VERSION 5.7 ;
  NOWIREEXTENSIONATPIN ON ;
  DIVIDERCHAR "/" ;
  BUSBITCHARS "[]" ;
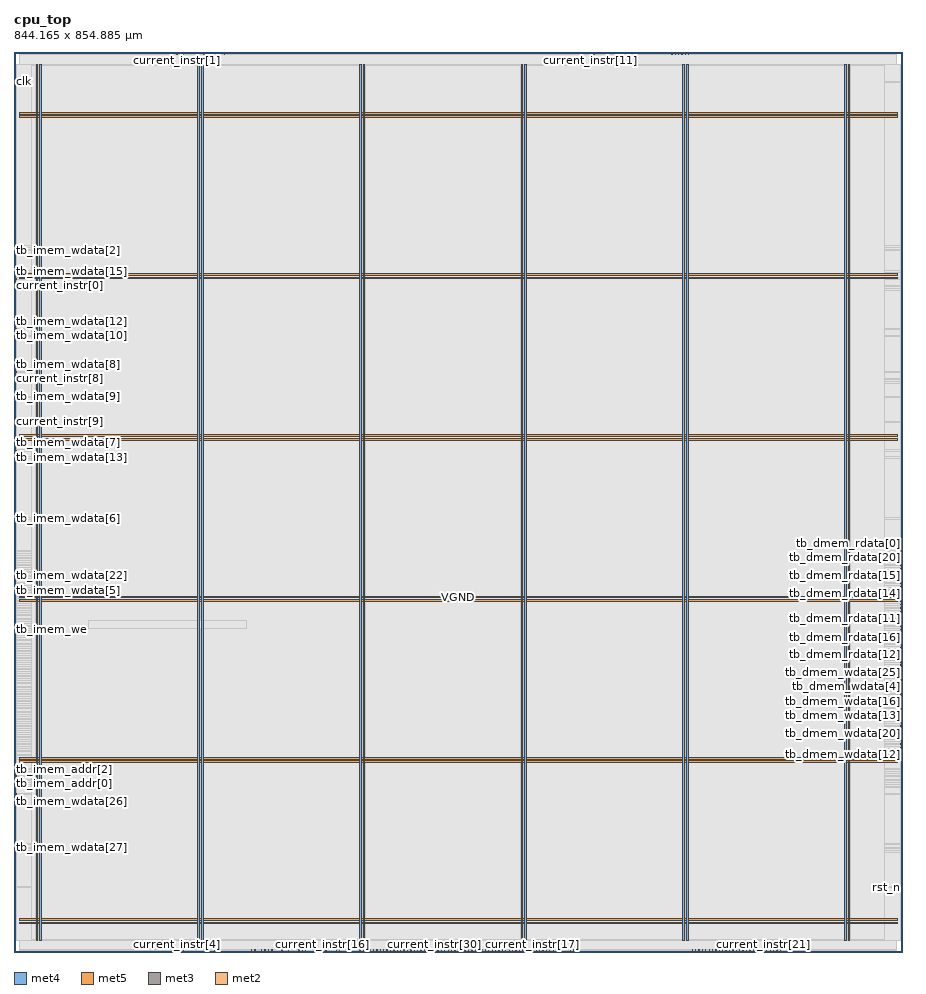
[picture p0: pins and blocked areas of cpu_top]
MACRO cpu_top
  CLASS BLOCK ;
  FOREIGN cpu_top ;
  ORIGIN 0.000 0.000 ;
  SIZE 844.165 BY 854.885 ;
  PIN VGND
    DIRECTION INOUT ;
    USE GROUND ;
    PORT
      LAYER met4 ;
        RECT 24.340 10.640 25.940 843.440 ;
    END
    PORT
      LAYER met4 ;
        RECT 177.940 10.640 179.540 843.440 ;
    END
    PORT
      LAYER met4 ;
        RECT 331.540 10.640 333.140 843.440 ;
    END
    PORT
      LAYER met4 ;
        RECT 485.140 10.640 486.740 843.440 ;
    END
    PORT
      LAYER met4 ;
        RECT 638.740 10.640 640.340 843.440 ;
    END
    PORT
      LAYER met4 ;
        RECT 792.340 10.640 793.940 843.440 ;
    END
    PORT
      LAYER met5 ;
        RECT 5.280 30.030 838.820 31.630 ;
    END
    PORT
      LAYER met5 ;
        RECT 5.280 183.210 838.820 184.810 ;
    END
    PORT
      LAYER met5 ;
        RECT 5.280 336.390 838.820 337.990 ;
    END
    PORT
      LAYER met5 ;
        RECT 5.280 489.570 838.820 491.170 ;
    END
    PORT
      LAYER met5 ;
        RECT 5.280 642.750 838.820 644.350 ;
    END
    PORT
      LAYER met5 ;
        RECT 5.280 795.930 838.820 797.530 ;
    END
  END VGND
  PIN VPWR
    DIRECTION INOUT ;
    USE POWER ;
    PORT
      LAYER met4 ;
        RECT 21.040 10.640 22.640 843.440 ;
    END
    PORT
      LAYER met4 ;
        RECT 174.640 10.640 176.240 843.440 ;
    END
    PORT
      LAYER met4 ;
        RECT 328.240 10.640 329.840 843.440 ;
    END
    PORT
      LAYER met4 ;
        RECT 481.840 10.640 483.440 843.440 ;
    END
    PORT
      LAYER met4 ;
        RECT 635.440 10.640 637.040 843.440 ;
    END
    PORT
      LAYER met4 ;
        RECT 789.040 10.640 790.640 843.440 ;
    END
    PORT
      LAYER met5 ;
        RECT 5.280 26.730 838.820 28.330 ;
    END
    PORT
      LAYER met5 ;
        RECT 5.280 179.910 838.820 181.510 ;
    END
    PORT
      LAYER met5 ;
        RECT 5.280 333.090 838.820 334.690 ;
    END
    PORT
      LAYER met5 ;
        RECT 5.280 486.270 838.820 487.870 ;
    END
    PORT
      LAYER met5 ;
        RECT 5.280 639.450 838.820 641.050 ;
    END
    PORT
      LAYER met5 ;
        RECT 5.280 792.630 838.820 794.230 ;
    END
  END VPWR
  PIN clk
    DIRECTION INPUT ;
    USE SIGNAL ;
    ANTENNAGATEAREA 0.852000 ;
    ANTENNADIFFAREA 0.434700 ;
    PORT
      LAYER met3 ;
        RECT 0.000 826.240 2.000 826.840 ;
    END
  END clk
  PIN current_instr[0]
    DIRECTION OUTPUT ;
    USE SIGNAL ;
    ANTENNADIFFAREA 0.445500 ;
    PORT
      LAYER met3 ;
        RECT 0.000 632.440 2.000 633.040 ;
    END
  END current_instr[0]
  PIN current_instr[10]
    DIRECTION OUTPUT ;
    USE SIGNAL ;
    ANTENNADIFFAREA 0.795200 ;
    PORT
      LAYER met2 ;
        RECT 499.190 0.000 499.470 2.000 ;
    END
  END current_instr[10]
  PIN current_instr[11]
    DIRECTION OUTPUT ;
    USE SIGNAL ;
    ANTENNADIFFAREA 0.795200 ;
    PORT
      LAYER met2 ;
        RECT 547.490 852.885 547.770 854.885 ;
    END
  END current_instr[11]
  PIN current_instr[12]
    DIRECTION OUTPUT ;
    USE SIGNAL ;
    ANTENNADIFFAREA 0.795200 ;
    PORT
      LAYER met2 ;
        RECT 254.470 0.000 254.750 2.000 ;
    END
  END current_instr[12]
  PIN current_instr[13]
    DIRECTION OUTPUT ;
    USE SIGNAL ;
    ANTENNADIFFAREA 0.795200 ;
    PORT
      LAYER met2 ;
        RECT 309.210 0.000 309.490 2.000 ;
    END
  END current_instr[13]
  PIN current_instr[14]
    DIRECTION OUTPUT ;
    USE SIGNAL ;
    ANTENNADIFFAREA 0.795200 ;
    PORT
      LAYER met2 ;
        RECT 505.630 0.000 505.910 2.000 ;
    END
  END current_instr[14]
  PIN current_instr[15]
    DIRECTION OUTPUT ;
    USE SIGNAL ;
    ANTENNADIFFAREA 0.795200 ;
    PORT
      LAYER met2 ;
        RECT 550.710 852.885 550.990 854.885 ;
    END
  END current_instr[15]
  PIN current_instr[16]
    DIRECTION OUTPUT ;
    USE SIGNAL ;
    ANTENNADIFFAREA 0.795200 ;
    PORT
      LAYER met2 ;
        RECT 293.110 0.000 293.390 2.000 ;
    END
  END current_instr[16]
  PIN current_instr[17]
    DIRECTION OUTPUT ;
    USE SIGNAL ;
    ANTENNADIFFAREA 0.795200 ;
    PORT
      LAYER met2 ;
        RECT 492.750 0.000 493.030 2.000 ;
    END
  END current_instr[17]
  PIN current_instr[18]
    DIRECTION OUTPUT ;
    USE SIGNAL ;
    ANTENNADIFFAREA 0.795200 ;
    PORT
      LAYER met2 ;
        RECT 508.850 0.000 509.130 2.000 ;
    END
  END current_instr[18]
  PIN current_instr[19]
    DIRECTION OUTPUT ;
    USE SIGNAL ;
    ANTENNADIFFAREA 0.795200 ;
    PORT
      LAYER met2 ;
        RECT 489.530 0.000 489.810 2.000 ;
    END
  END current_instr[19]
  PIN current_instr[1]
    DIRECTION OUTPUT ;
    USE SIGNAL ;
    ANTENNADIFFAREA 0.795200 ;
    PORT
      LAYER met2 ;
        RECT 154.650 852.885 154.930 854.885 ;
    END
  END current_instr[1]
  PIN current_instr[20]
    DIRECTION OUTPUT ;
    USE SIGNAL ;
    ANTENNADIFFAREA 0.795200 ;
    PORT
      LAYER met2 ;
        RECT 434.790 0.000 435.070 2.000 ;
    END
  END current_instr[20]
  PIN current_instr[21]
    DIRECTION OUTPUT ;
    USE SIGNAL ;
    ANTENNADIFFAREA 0.795200 ;
    PORT
      LAYER met2 ;
        RECT 711.710 0.000 711.990 2.000 ;
    END
  END current_instr[21]
  PIN current_instr[22]
    DIRECTION OUTPUT ;
    USE SIGNAL ;
    ANTENNADIFFAREA 0.795200 ;
    PORT
      LAYER met2 ;
        RECT 418.690 0.000 418.970 2.000 ;
    END
  END current_instr[22]
  PIN current_instr[23]
    DIRECTION OUTPUT ;
    USE SIGNAL ;
    ANTENNADIFFAREA 0.795200 ;
    PORT
      LAYER met2 ;
        RECT 479.870 0.000 480.150 2.000 ;
    END
  END current_instr[23]
  PIN current_instr[24]
    DIRECTION OUTPUT ;
    USE SIGNAL ;
    ANTENNADIFFAREA 0.795200 ;
    PORT
      LAYER met2 ;
        RECT 476.650 0.000 476.930 2.000 ;
    END
  END current_instr[24]
  PIN current_instr[25]
    DIRECTION OUTPUT ;
    USE SIGNAL ;
    ANTENNADIFFAREA 0.795200 ;
    PORT
      LAYER met2 ;
        RECT 483.090 0.000 483.370 2.000 ;
    END
  END current_instr[25]
  PIN current_instr[26]
    DIRECTION OUTPUT ;
    USE SIGNAL ;
    ANTENNADIFFAREA 0.795200 ;
    PORT
      LAYER met2 ;
        RECT 441.230 0.000 441.510 2.000 ;
    END
  END current_instr[26]
  PIN current_instr[27]
    DIRECTION OUTPUT ;
    USE SIGNAL ;
    ANTENNADIFFAREA 0.795200 ;
    PORT
      LAYER met2 ;
        RECT 438.010 0.000 438.290 2.000 ;
    END
  END current_instr[27]
  PIN current_instr[28]
    DIRECTION OUTPUT ;
    USE SIGNAL ;
    ANTENNADIFFAREA 0.795200 ;
    PORT
      LAYER met2 ;
        RECT 409.030 0.000 409.310 2.000 ;
    END
  END current_instr[28]
  PIN current_instr[29]
    DIRECTION OUTPUT ;
    USE SIGNAL ;
    ANTENNADIFFAREA 0.795200 ;
    PORT
      LAYER met2 ;
        RECT 425.130 0.000 425.410 2.000 ;
    END
  END current_instr[29]
  PIN current_instr[2]
    DIRECTION OUTPUT ;
    USE SIGNAL ;
    ANTENNADIFFAREA 0.795200 ;
    PORT
      LAYER met2 ;
        RECT 199.730 852.885 200.010 854.885 ;
    END
  END current_instr[2]
  PIN current_instr[30]
    DIRECTION OUTPUT ;
    USE SIGNAL ;
    ANTENNADIFFAREA 0.795200 ;
    PORT
      LAYER met2 ;
        RECT 399.370 0.000 399.650 2.000 ;
    END
  END current_instr[30]
  PIN current_instr[31]
    DIRECTION OUTPUT ;
    USE SIGNAL ;
    ANTENNADIFFAREA 0.795200 ;
    PORT
      LAYER met2 ;
        RECT 402.590 0.000 402.870 2.000 ;
    END
  END current_instr[31]
  PIN current_instr[3]
    DIRECTION OUTPUT ;
    USE SIGNAL ;
    ANTENNADIFFAREA 0.795200 ;
    PORT
      LAYER met2 ;
        RECT 161.090 852.885 161.370 854.885 ;
    END
  END current_instr[3]
  PIN current_instr[4]
    DIRECTION OUTPUT ;
    USE SIGNAL ;
    ANTENNADIFFAREA 0.795200 ;
    PORT
      LAYER met2 ;
        RECT 154.650 0.000 154.930 2.000 ;
    END
  END current_instr[4]
  PIN current_instr[5]
    DIRECTION OUTPUT ;
    USE SIGNAL ;
    ANTENNADIFFAREA 0.795200 ;
    PORT
      LAYER met2 ;
        RECT 157.870 0.000 158.150 2.000 ;
    END
  END current_instr[5]
  PIN current_instr[6]
    DIRECTION OUTPUT ;
    USE SIGNAL ;
    ANTENNADIFFAREA 0.795200 ;
    PORT
      LAYER met2 ;
        RECT 235.150 0.000 235.430 2.000 ;
    END
  END current_instr[6]
  PIN current_instr[7]
    DIRECTION OUTPUT ;
    USE SIGNAL ;
    ANTENNADIFFAREA 0.795200 ;
    PORT
      LAYER met2 ;
        RECT 161.090 0.000 161.370 2.000 ;
    END
  END current_instr[7]
  PIN current_instr[8]
    DIRECTION OUTPUT ;
    USE SIGNAL ;
    ANTENNADIFFAREA 0.445500 ;
    PORT
      LAYER met3 ;
        RECT 0.000 544.040 2.000 544.640 ;
    END
  END current_instr[8]
  PIN current_instr[9]
    DIRECTION OUTPUT ;
    USE SIGNAL ;
    ANTENNADIFFAREA 0.445500 ;
    PORT
      LAYER met3 ;
        RECT 0.000 503.240 2.000 503.840 ;
    END
  END current_instr[9]
  PIN pc_out[0]
    DIRECTION OUTPUT ;
    USE SIGNAL ;
    ANTENNADIFFAREA 0.795200 ;
    PORT
      LAYER met2 ;
        RECT 270.570 0.000 270.850 2.000 ;
    END
  END pc_out[0]
  PIN pc_out[10]
    DIRECTION OUTPUT ;
    USE SIGNAL ;
    ANTENNADIFFAREA 0.795200 ;
    PORT
      LAYER met2 ;
        RECT 328.530 0.000 328.810 2.000 ;
    END
  END pc_out[10]
  PIN pc_out[11]
    DIRECTION OUTPUT ;
    USE SIGNAL ;
    ANTENNADIFFAREA 0.795200 ;
    PORT
      LAYER met2 ;
        RECT 389.710 0.000 389.990 2.000 ;
    END
  END pc_out[11]
  PIN pc_out[12]
    DIRECTION OUTPUT ;
    USE SIGNAL ;
    ANTENNADIFFAREA 0.795200 ;
    PORT
      LAYER met2 ;
        RECT 412.250 0.000 412.530 2.000 ;
    END
  END pc_out[12]
  PIN pc_out[13]
    DIRECTION OUTPUT ;
    USE SIGNAL ;
    ANTENNADIFFAREA 0.795200 ;
    PORT
      LAYER met2 ;
        RECT 392.930 0.000 393.210 2.000 ;
    END
  END pc_out[13]
  PIN pc_out[14]
    DIRECTION OUTPUT ;
    USE SIGNAL ;
    ANTENNADIFFAREA 0.795200 ;
    PORT
      LAYER met2 ;
        RECT 334.970 0.000 335.250 2.000 ;
    END
  END pc_out[14]
  PIN pc_out[15]
    DIRECTION OUTPUT ;
    USE SIGNAL ;
    ANTENNADIFFAREA 0.795200 ;
    PORT
      LAYER met2 ;
        RECT 331.750 0.000 332.030 2.000 ;
    END
  END pc_out[15]
  PIN pc_out[16]
    DIRECTION OUTPUT ;
    USE SIGNAL ;
    ANTENNADIFFAREA 0.795200 ;
    PORT
      LAYER met2 ;
        RECT 338.190 0.000 338.470 2.000 ;
    END
  END pc_out[16]
  PIN pc_out[17]
    DIRECTION OUTPUT ;
    USE SIGNAL ;
    ANTENNADIFFAREA 0.795200 ;
    PORT
      LAYER met2 ;
        RECT 357.510 0.000 357.790 2.000 ;
    END
  END pc_out[17]
  PIN pc_out[18]
    DIRECTION OUTPUT ;
    USE SIGNAL ;
    ANTENNADIFFAREA 0.795200 ;
    PORT
      LAYER met2 ;
        RECT 373.610 0.000 373.890 2.000 ;
    END
  END pc_out[18]
  PIN pc_out[19]
    DIRECTION OUTPUT ;
    USE SIGNAL ;
    ANTENNADIFFAREA 0.795200 ;
    PORT
      LAYER met2 ;
        RECT 370.390 0.000 370.670 2.000 ;
    END
  END pc_out[19]
  PIN pc_out[1]
    DIRECTION OUTPUT ;
    USE SIGNAL ;
    ANTENNADIFFAREA 0.795200 ;
    PORT
      LAYER met2 ;
        RECT 238.370 0.000 238.650 2.000 ;
    END
  END pc_out[1]
  PIN pc_out[20]
    DIRECTION OUTPUT ;
    USE SIGNAL ;
    ANTENNADIFFAREA 0.795200 ;
    PORT
      LAYER met2 ;
        RECT 363.950 0.000 364.230 2.000 ;
    END
  END pc_out[20]
  PIN pc_out[21]
    DIRECTION OUTPUT ;
    USE SIGNAL ;
    ANTENNADIFFAREA 0.795200 ;
    PORT
      LAYER met2 ;
        RECT 376.830 0.000 377.110 2.000 ;
    END
  END pc_out[21]
  PIN pc_out[22]
    DIRECTION OUTPUT ;
    USE SIGNAL ;
    ANTENNADIFFAREA 0.795200 ;
    PORT
      LAYER met2 ;
        RECT 341.410 0.000 341.690 2.000 ;
    END
  END pc_out[22]
  PIN pc_out[23]
    DIRECTION OUTPUT ;
    USE SIGNAL ;
    ANTENNADIFFAREA 0.795200 ;
    PORT
      LAYER met2 ;
        RECT 380.050 0.000 380.330 2.000 ;
    END
  END pc_out[23]
  PIN pc_out[24]
    DIRECTION OUTPUT ;
    USE SIGNAL ;
    ANTENNADIFFAREA 0.795200 ;
    PORT
      LAYER met2 ;
        RECT 383.270 0.000 383.550 2.000 ;
    END
  END pc_out[24]
  PIN pc_out[25]
    DIRECTION OUTPUT ;
    USE SIGNAL ;
    ANTENNADIFFAREA 0.795200 ;
    PORT
      LAYER met2 ;
        RECT 386.490 0.000 386.770 2.000 ;
    END
  END pc_out[25]
  PIN pc_out[26]
    DIRECTION OUTPUT ;
    USE SIGNAL ;
    ANTENNADIFFAREA 0.795200 ;
    PORT
      LAYER met2 ;
        RECT 415.470 0.000 415.750 2.000 ;
    END
  END pc_out[26]
  PIN pc_out[27]
    DIRECTION OUTPUT ;
    USE SIGNAL ;
    ANTENNADIFFAREA 0.795200 ;
    PORT
      LAYER met2 ;
        RECT 431.570 0.000 431.850 2.000 ;
    END
  END pc_out[27]
  PIN pc_out[28]
    DIRECTION OUTPUT ;
    USE SIGNAL ;
    ANTENNADIFFAREA 0.795200 ;
    PORT
      LAYER met2 ;
        RECT 421.910 0.000 422.190 2.000 ;
    END
  END pc_out[28]
  PIN pc_out[29]
    DIRECTION OUTPUT ;
    USE SIGNAL ;
    ANTENNADIFFAREA 0.795200 ;
    PORT
      LAYER met2 ;
        RECT 405.810 0.000 406.090 2.000 ;
    END
  END pc_out[29]
  PIN pc_out[2]
    DIRECTION OUTPUT ;
    USE SIGNAL ;
    ANTENNADIFFAREA 0.795200 ;
    PORT
      LAYER met2 ;
        RECT 241.590 0.000 241.870 2.000 ;
    END
  END pc_out[2]
  PIN pc_out[30]
    DIRECTION OUTPUT ;
    USE SIGNAL ;
    ANTENNADIFFAREA 0.795200 ;
    PORT
      LAYER met2 ;
        RECT 396.150 0.000 396.430 2.000 ;
    END
  END pc_out[30]
  PIN pc_out[31]
    DIRECTION OUTPUT ;
    USE SIGNAL ;
    ANTENNADIFFAREA 0.795200 ;
    PORT
      LAYER met2 ;
        RECT 428.350 0.000 428.630 2.000 ;
    END
  END pc_out[31]
  PIN pc_out[3]
    DIRECTION OUTPUT ;
    USE SIGNAL ;
    ANTENNADIFFAREA 0.795200 ;
    PORT
      LAYER met2 ;
        RECT 244.810 0.000 245.090 2.000 ;
    END
  END pc_out[3]
  PIN pc_out[4]
    DIRECTION OUTPUT ;
    USE SIGNAL ;
    ANTENNADIFFAREA 0.795200 ;
    PORT
      LAYER met2 ;
        RECT 225.490 0.000 225.770 2.000 ;
    END
  END pc_out[4]
  PIN pc_out[5]
    DIRECTION OUTPUT ;
    USE SIGNAL ;
    ANTENNADIFFAREA 0.795200 ;
    PORT
      LAYER met2 ;
        RECT 228.710 0.000 228.990 2.000 ;
    END
  END pc_out[5]
  PIN pc_out[6]
    DIRECTION OUTPUT ;
    USE SIGNAL ;
    ANTENNADIFFAREA 0.795200 ;
    PORT
      LAYER met2 ;
        RECT 344.630 0.000 344.910 2.000 ;
    END
  END pc_out[6]
  PIN pc_out[7]
    DIRECTION OUTPUT ;
    USE SIGNAL ;
    ANTENNADIFFAREA 0.795200 ;
    PORT
      LAYER met2 ;
        RECT 354.290 0.000 354.570 2.000 ;
    END
  END pc_out[7]
  PIN pc_out[8]
    DIRECTION OUTPUT ;
    USE SIGNAL ;
    ANTENNADIFFAREA 0.795200 ;
    PORT
      LAYER met2 ;
        RECT 360.730 0.000 361.010 2.000 ;
    END
  END pc_out[8]
  PIN pc_out[9]
    DIRECTION OUTPUT ;
    USE SIGNAL ;
    ANTENNADIFFAREA 0.795200 ;
    PORT
      LAYER met2 ;
        RECT 367.170 0.000 367.450 2.000 ;
    END
  END pc_out[9]
  PIN rst_n
    DIRECTION INPUT ;
    USE SIGNAL ;
    ANTENNAGATEAREA 0.213000 ;
    ANTENNADIFFAREA 0.434700 ;
    PORT
      LAYER met3 ;
        RECT 842.165 61.240 844.165 61.840 ;
    END
  END rst_n
  PIN tb_dmem_addr[0]
    DIRECTION INPUT ;
    USE SIGNAL ;
    ANTENNAGATEAREA 0.213000 ;
    ANTENNADIFFAREA 0.434700 ;
    PORT
      LAYER met2 ;
        RECT 634.430 852.885 634.710 854.885 ;
    END
  END tb_dmem_addr[0]
  PIN tb_dmem_addr[1]
    DIRECTION INPUT ;
    USE SIGNAL ;
    ANTENNAGATEAREA 0.213000 ;
    ANTENNADIFFAREA 0.434700 ;
    PORT
      LAYER met2 ;
        RECT 631.210 852.885 631.490 854.885 ;
    END
  END tb_dmem_addr[1]
  PIN tb_dmem_addr[2]
    DIRECTION INPUT ;
    USE SIGNAL ;
    ANTENNAGATEAREA 0.213000 ;
    ANTENNADIFFAREA 0.434700 ;
    PORT
      LAYER met2 ;
        RECT 640.870 852.885 641.150 854.885 ;
    END
  END tb_dmem_addr[2]
  PIN tb_dmem_addr[3]
    DIRECTION INPUT ;
    USE SIGNAL ;
    ANTENNAGATEAREA 0.213000 ;
    ANTENNADIFFAREA 0.434700 ;
    PORT
      LAYER met2 ;
        RECT 637.650 852.885 637.930 854.885 ;
    END
  END tb_dmem_addr[3]
  PIN tb_dmem_addr[4]
    DIRECTION INPUT ;
    USE SIGNAL ;
    ANTENNAGATEAREA 0.159000 ;
    ANTENNADIFFAREA 0.434700 ;
    PORT
      LAYER met2 ;
        RECT 624.770 852.885 625.050 854.885 ;
    END
  END tb_dmem_addr[4]
  PIN tb_dmem_addr[5]
    DIRECTION INPUT ;
    USE SIGNAL ;
    ANTENNAGATEAREA 0.159000 ;
    ANTENNADIFFAREA 0.434700 ;
    PORT
      LAYER met2 ;
        RECT 627.990 852.885 628.270 854.885 ;
    END
  END tb_dmem_addr[5]
  PIN tb_dmem_rdata[0]
    DIRECTION OUTPUT ;
    USE SIGNAL ;
    ANTENNADIFFAREA 0.445500 ;
    PORT
      LAYER met3 ;
        RECT 842.165 380.840 844.165 381.440 ;
    END
  END tb_dmem_rdata[0]
  PIN tb_dmem_rdata[10]
    DIRECTION OUTPUT ;
    USE SIGNAL ;
    ANTENNADIFFAREA 0.445500 ;
    PORT
      LAYER met3 ;
        RECT 842.165 360.440 844.165 361.040 ;
    END
  END tb_dmem_rdata[10]
  PIN tb_dmem_rdata[11]
    DIRECTION OUTPUT ;
    USE SIGNAL ;
    ANTENNADIFFAREA 0.445500 ;
    PORT
      LAYER met3 ;
        RECT 842.165 316.240 844.165 316.840 ;
    END
  END tb_dmem_rdata[11]
  PIN tb_dmem_rdata[12]
    DIRECTION OUTPUT ;
    USE SIGNAL ;
    ANTENNADIFFAREA 0.445500 ;
    PORT
      LAYER met3 ;
        RECT 842.165 282.240 844.165 282.840 ;
    END
  END tb_dmem_rdata[12]
  PIN tb_dmem_rdata[13]
    DIRECTION OUTPUT ;
    USE SIGNAL ;
    ANTENNADIFFAREA 0.445500 ;
    PORT
      LAYER met3 ;
        RECT 842.165 295.840 844.165 296.440 ;
    END
  END tb_dmem_rdata[13]
  PIN tb_dmem_rdata[14]
    DIRECTION OUTPUT ;
    USE SIGNAL ;
    ANTENNADIFFAREA 0.445500 ;
    PORT
      LAYER met3 ;
        RECT 842.165 340.040 844.165 340.640 ;
    END
  END tb_dmem_rdata[14]
  PIN tb_dmem_rdata[15]
    DIRECTION OUTPUT ;
    USE SIGNAL ;
    ANTENNADIFFAREA 0.445500 ;
    PORT
      LAYER met3 ;
        RECT 842.165 357.040 844.165 357.640 ;
    END
  END tb_dmem_rdata[15]
  PIN tb_dmem_rdata[16]
    DIRECTION OUTPUT ;
    USE SIGNAL ;
    ANTENNADIFFAREA 0.445500 ;
    PORT
      LAYER met3 ;
        RECT 842.165 306.040 844.165 306.640 ;
    END
  END tb_dmem_rdata[16]
  PIN tb_dmem_rdata[17]
    DIRECTION OUTPUT ;
    USE SIGNAL ;
    ANTENNADIFFAREA 0.445500 ;
    PORT
      LAYER met3 ;
        RECT 842.165 323.040 844.165 323.640 ;
    END
  END tb_dmem_rdata[17]
  PIN tb_dmem_rdata[18]
    DIRECTION OUTPUT ;
    USE SIGNAL ;
    ANTENNADIFFAREA 0.445500 ;
    PORT
      LAYER met3 ;
        RECT 842.165 370.640 844.165 371.240 ;
    END
  END tb_dmem_rdata[18]
  PIN tb_dmem_rdata[19]
    DIRECTION OUTPUT ;
    USE SIGNAL ;
    ANTENNADIFFAREA 0.445500 ;
    PORT
      LAYER met3 ;
        RECT 842.165 336.640 844.165 337.240 ;
    END
  END tb_dmem_rdata[19]
  PIN tb_dmem_rdata[1]
    DIRECTION OUTPUT ;
    USE SIGNAL ;
    ANTENNADIFFAREA 0.795200 ;
    PORT
      LAYER met2 ;
        RECT 447.670 0.000 447.950 2.000 ;
    END
  END tb_dmem_rdata[1]
  PIN tb_dmem_rdata[20]
    DIRECTION OUTPUT ;
    USE SIGNAL ;
    ANTENNADIFFAREA 0.445500 ;
    PORT
      LAYER met3 ;
        RECT 842.165 367.240 844.165 367.840 ;
    END
  END tb_dmem_rdata[20]
  PIN tb_dmem_rdata[21]
    DIRECTION OUTPUT ;
    USE SIGNAL ;
    ANTENNADIFFAREA 0.445500 ;
    PORT
      LAYER met3 ;
        RECT 842.165 289.040 844.165 289.640 ;
    END
  END tb_dmem_rdata[21]
  PIN tb_dmem_rdata[22]
    DIRECTION OUTPUT ;
    USE SIGNAL ;
    ANTENNADIFFAREA 0.445500 ;
    PORT
      LAYER met3 ;
        RECT 842.165 333.240 844.165 333.840 ;
    END
  END tb_dmem_rdata[22]
  PIN tb_dmem_rdata[23]
    DIRECTION OUTPUT ;
    USE SIGNAL ;
    ANTENNADIFFAREA 0.445500 ;
    PORT
      LAYER met3 ;
        RECT 842.165 326.440 844.165 327.040 ;
    END
  END tb_dmem_rdata[23]
  PIN tb_dmem_rdata[24]
    DIRECTION OUTPUT ;
    USE SIGNAL ;
    ANTENNADIFFAREA 0.445500 ;
    PORT
      LAYER met3 ;
        RECT 842.165 312.840 844.165 313.440 ;
    END
  END tb_dmem_rdata[24]
  PIN tb_dmem_rdata[25]
    DIRECTION OUTPUT ;
    USE SIGNAL ;
    ANTENNADIFFAREA 0.445500 ;
    PORT
      LAYER met3 ;
        RECT 842.165 302.640 844.165 303.240 ;
    END
  END tb_dmem_rdata[25]
  PIN tb_dmem_rdata[26]
    DIRECTION OUTPUT ;
    USE SIGNAL ;
    ANTENNADIFFAREA 0.445500 ;
    PORT
      LAYER met3 ;
        RECT 842.165 299.240 844.165 299.840 ;
    END
  END tb_dmem_rdata[26]
  PIN tb_dmem_rdata[27]
    DIRECTION OUTPUT ;
    USE SIGNAL ;
    ANTENNADIFFAREA 0.445500 ;
    PORT
      LAYER met3 ;
        RECT 842.165 374.040 844.165 374.640 ;
    END
  END tb_dmem_rdata[27]
  PIN tb_dmem_rdata[28]
    DIRECTION OUTPUT ;
    USE SIGNAL ;
    ANTENNADIFFAREA 0.445500 ;
    PORT
      LAYER met3 ;
        RECT 842.165 285.640 844.165 286.240 ;
    END
  END tb_dmem_rdata[28]
  PIN tb_dmem_rdata[29]
    DIRECTION OUTPUT ;
    USE SIGNAL ;
    ANTENNADIFFAREA 0.445500 ;
    PORT
      LAYER met3 ;
        RECT 842.165 353.640 844.165 354.240 ;
    END
  END tb_dmem_rdata[29]
  PIN tb_dmem_rdata[2]
    DIRECTION OUTPUT ;
    USE SIGNAL ;
    ANTENNADIFFAREA 0.795200 ;
    PORT
      LAYER met2 ;
        RECT 444.450 0.000 444.730 2.000 ;
    END
  END tb_dmem_rdata[2]
  PIN tb_dmem_rdata[30]
    DIRECTION OUTPUT ;
    USE SIGNAL ;
    ANTENNADIFFAREA 0.445500 ;
    PORT
      LAYER met3 ;
        RECT 842.165 350.240 844.165 350.840 ;
    END
  END tb_dmem_rdata[30]
  PIN tb_dmem_rdata[31]
    DIRECTION OUTPUT ;
    USE SIGNAL ;
    ANTENNADIFFAREA 0.445500 ;
    PORT
      LAYER met3 ;
        RECT 842.165 343.440 844.165 344.040 ;
    END
  END tb_dmem_rdata[31]
  PIN tb_dmem_rdata[3]
    DIRECTION OUTPUT ;
    USE SIGNAL ;
    ANTENNADIFFAREA 0.445500 ;
    PORT
      LAYER met3 ;
        RECT 842.165 309.440 844.165 310.040 ;
    END
  END tb_dmem_rdata[3]
  PIN tb_dmem_rdata[4]
    DIRECTION OUTPUT ;
    USE SIGNAL ;
    ANTENNADIFFAREA 0.795200 ;
    PORT
      LAYER met2 ;
        RECT 473.430 0.000 473.710 2.000 ;
    END
  END tb_dmem_rdata[4]
  PIN tb_dmem_rdata[5]
    DIRECTION OUTPUT ;
    USE SIGNAL ;
    ANTENNADIFFAREA 0.445500 ;
    PORT
      LAYER met3 ;
        RECT 842.165 329.840 844.165 330.440 ;
    END
  END tb_dmem_rdata[5]
  PIN tb_dmem_rdata[6]
    DIRECTION OUTPUT ;
    USE SIGNAL ;
    ANTENNADIFFAREA 0.445500 ;
    PORT
      LAYER met3 ;
        RECT 842.165 319.640 844.165 320.240 ;
    END
  END tb_dmem_rdata[6]
  PIN tb_dmem_rdata[7]
    DIRECTION OUTPUT ;
    USE SIGNAL ;
    ANTENNADIFFAREA 0.795200 ;
    PORT
      LAYER met2 ;
        RECT 457.330 0.000 457.610 2.000 ;
    END
  END tb_dmem_rdata[7]
  PIN tb_dmem_rdata[8]
    DIRECTION OUTPUT ;
    USE SIGNAL ;
    ANTENNADIFFAREA 0.445500 ;
    PORT
      LAYER met3 ;
        RECT 842.165 363.840 844.165 364.440 ;
    END
  END tb_dmem_rdata[8]
  PIN tb_dmem_rdata[9]
    DIRECTION OUTPUT ;
    USE SIGNAL ;
    ANTENNADIFFAREA 0.445500 ;
    PORT
      LAYER met3 ;
        RECT 842.165 292.440 844.165 293.040 ;
    END
  END tb_dmem_rdata[9]
  PIN tb_dmem_re
    DIRECTION INPUT ;
    USE SIGNAL ;
    ANTENNAGATEAREA 0.213000 ;
    ANTENNADIFFAREA 0.434700 ;
    PORT
      LAYER met3 ;
        RECT 842.165 346.840 844.165 347.440 ;
    END
  END tb_dmem_re
  PIN tb_dmem_wdata[0]
    DIRECTION INPUT ;
    USE SIGNAL ;
    ANTENNAGATEAREA 0.213000 ;
    ANTENNADIFFAREA 0.434700 ;
    PORT
      LAYER met2 ;
        RECT 463.770 0.000 464.050 2.000 ;
    END
  END tb_dmem_wdata[0]
  PIN tb_dmem_wdata[10]
    DIRECTION INPUT ;
    USE SIGNAL ;
    ANTENNAGATEAREA 0.213000 ;
    ANTENNADIFFAREA 0.434700 ;
    PORT
      LAYER met3 ;
        RECT 842.165 183.640 844.165 184.240 ;
    END
  END tb_dmem_wdata[10]
  PIN tb_dmem_wdata[11]
    DIRECTION INPUT ;
    USE SIGNAL ;
    ANTENNAGATEAREA 0.213000 ;
    ANTENNADIFFAREA 0.434700 ;
    PORT
      LAYER met3 ;
        RECT 842.165 275.440 844.165 276.040 ;
    END
  END tb_dmem_wdata[11]
  PIN tb_dmem_wdata[12]
    DIRECTION INPUT ;
    USE SIGNAL ;
    ANTENNAGATEAREA 0.159000 ;
    ANTENNADIFFAREA 0.434700 ;
    PORT
      LAYER met3 ;
        RECT 842.165 187.040 844.165 187.640 ;
    END
  END tb_dmem_wdata[12]
  PIN tb_dmem_wdata[13]
    DIRECTION INPUT ;
    USE SIGNAL ;
    ANTENNAGATEAREA 0.159000 ;
    ANTENNADIFFAREA 0.434700 ;
    PORT
      LAYER met3 ;
        RECT 842.165 224.440 844.165 225.040 ;
    END
  END tb_dmem_wdata[13]
  PIN tb_dmem_wdata[14]
    DIRECTION INPUT ;
    USE SIGNAL ;
    ANTENNAGATEAREA 0.213000 ;
    ANTENNADIFFAREA 0.434700 ;
    PORT
      LAYER met3 ;
        RECT 842.165 227.840 844.165 228.440 ;
    END
  END tb_dmem_wdata[14]
  PIN tb_dmem_wdata[15]
    DIRECTION INPUT ;
    USE SIGNAL ;
    ANTENNAGATEAREA 0.213000 ;
    ANTENNADIFFAREA 0.434700 ;
    PORT
      LAYER met3 ;
        RECT 842.165 221.040 844.165 221.640 ;
    END
  END tb_dmem_wdata[15]
  PIN tb_dmem_wdata[16]
    DIRECTION INPUT ;
    USE SIGNAL ;
    ANTENNAGATEAREA 0.213000 ;
    ANTENNADIFFAREA 0.434700 ;
    PORT
      LAYER met3 ;
        RECT 842.165 238.040 844.165 238.640 ;
    END
  END tb_dmem_wdata[16]
  PIN tb_dmem_wdata[17]
    DIRECTION INPUT ;
    USE SIGNAL ;
    ANTENNAGATEAREA 0.213000 ;
    ANTENNADIFFAREA 0.434700 ;
    PORT
      LAYER met3 ;
        RECT 842.165 255.040 844.165 255.640 ;
    END
  END tb_dmem_wdata[17]
  PIN tb_dmem_wdata[18]
    DIRECTION INPUT ;
    USE SIGNAL ;
    ANTENNAGATEAREA 0.213000 ;
    ANTENNADIFFAREA 0.434700 ;
    PORT
      LAYER met3 ;
        RECT 842.165 190.440 844.165 191.040 ;
    END
  END tb_dmem_wdata[18]
  PIN tb_dmem_wdata[19]
    DIRECTION INPUT ;
    USE SIGNAL ;
    ANTENNAGATEAREA 0.213000 ;
    ANTENNADIFFAREA 0.434700 ;
    PORT
      LAYER met3 ;
        RECT 842.165 217.640 844.165 218.240 ;
    END
  END tb_dmem_wdata[19]
  PIN tb_dmem_wdata[1]
    DIRECTION INPUT ;
    USE SIGNAL ;
    ANTENNAGATEAREA 0.213000 ;
    ANTENNADIFFAREA 0.434700 ;
    PORT
      LAYER met2 ;
        RECT 454.110 0.000 454.390 2.000 ;
    END
  END tb_dmem_wdata[1]
  PIN tb_dmem_wdata[20]
    DIRECTION INPUT ;
    USE SIGNAL ;
    ANTENNAGATEAREA 0.213000 ;
    ANTENNADIFFAREA 0.434700 ;
    PORT
      LAYER met3 ;
        RECT 842.165 214.240 844.165 214.840 ;
    END
  END tb_dmem_wdata[20]
  PIN tb_dmem_wdata[21]
    DIRECTION INPUT ;
    USE SIGNAL ;
    ANTENNAGATEAREA 0.213000 ;
    ANTENNADIFFAREA 0.434700 ;
    PORT
      LAYER met3 ;
        RECT 842.165 210.840 844.165 211.440 ;
    END
  END tb_dmem_wdata[21]
  PIN tb_dmem_wdata[22]
    DIRECTION INPUT ;
    USE SIGNAL ;
    ANTENNAGATEAREA 0.126000 ;
    ANTENNADIFFAREA 0.434700 ;
    PORT
      LAYER met3 ;
        RECT 842.165 278.840 844.165 279.440 ;
    END
  END tb_dmem_wdata[22]
  PIN tb_dmem_wdata[23]
    DIRECTION INPUT ;
    USE SIGNAL ;
    ANTENNAGATEAREA 0.196500 ;
    ANTENNADIFFAREA 0.434700 ;
    PORT
      LAYER met3 ;
        RECT 842.165 258.440 844.165 259.040 ;
    END
  END tb_dmem_wdata[23]
  PIN tb_dmem_wdata[24]
    DIRECTION INPUT ;
    USE SIGNAL ;
    ANTENNAGATEAREA 0.196500 ;
    ANTENNADIFFAREA 0.434700 ;
    PORT
      LAYER met3 ;
        RECT 842.165 234.640 844.165 235.240 ;
    END
  END tb_dmem_wdata[24]
  PIN tb_dmem_wdata[25]
    DIRECTION INPUT ;
    USE SIGNAL ;
    ANTENNAGATEAREA 0.196500 ;
    ANTENNADIFFAREA 0.434700 ;
    PORT
      LAYER met3 ;
        RECT 842.165 265.240 844.165 265.840 ;
    END
  END tb_dmem_wdata[25]
  PIN tb_dmem_wdata[26]
    DIRECTION INPUT ;
    USE SIGNAL ;
    ANTENNAGATEAREA 0.213000 ;
    ANTENNADIFFAREA 0.434700 ;
    PORT
      LAYER met3 ;
        RECT 842.165 207.440 844.165 208.040 ;
    END
  END tb_dmem_wdata[26]
  PIN tb_dmem_wdata[27]
    DIRECTION INPUT ;
    USE SIGNAL ;
    ANTENNAGATEAREA 0.196500 ;
    ANTENNADIFFAREA 0.434700 ;
    PORT
      LAYER met3 ;
        RECT 842.165 261.840 844.165 262.440 ;
    END
  END tb_dmem_wdata[27]
  PIN tb_dmem_wdata[28]
    DIRECTION INPUT ;
    USE SIGNAL ;
    ANTENNAGATEAREA 0.126000 ;
    ANTENNADIFFAREA 0.434700 ;
    PORT
      LAYER met3 ;
        RECT 842.165 204.040 844.165 204.640 ;
    END
  END tb_dmem_wdata[28]
  PIN tb_dmem_wdata[29]
    DIRECTION INPUT ;
    USE SIGNAL ;
    ANTENNAGATEAREA 0.213000 ;
    ANTENNADIFFAREA 0.434700 ;
    PORT
      LAYER met3 ;
        RECT 842.165 200.640 844.165 201.240 ;
    END
  END tb_dmem_wdata[29]
  PIN tb_dmem_wdata[2]
    DIRECTION INPUT ;
    USE SIGNAL ;
    ANTENNAGATEAREA 0.213000 ;
    ANTENNADIFFAREA 0.434700 ;
    PORT
      LAYER met2 ;
        RECT 450.890 0.000 451.170 2.000 ;
    END
  END tb_dmem_wdata[2]
  PIN tb_dmem_wdata[30]
    DIRECTION INPUT ;
    USE SIGNAL ;
    ANTENNAGATEAREA 0.159000 ;
    ANTENNADIFFAREA 0.434700 ;
    PORT
      LAYER met3 ;
        RECT 842.165 241.440 844.165 242.040 ;
    END
  END tb_dmem_wdata[30]
  PIN tb_dmem_wdata[31]
    DIRECTION INPUT ;
    USE SIGNAL ;
    ANTENNAGATEAREA 0.159000 ;
    ANTENNADIFFAREA 0.434700 ;
    PORT
      LAYER met3 ;
        RECT 842.165 197.240 844.165 197.840 ;
    END
  END tb_dmem_wdata[31]
  PIN tb_dmem_wdata[3]
    DIRECTION INPUT ;
    USE SIGNAL ;
    ANTENNAGATEAREA 0.213000 ;
    ANTENNADIFFAREA 0.434700 ;
    PORT
      LAYER met3 ;
        RECT 842.165 193.840 844.165 194.440 ;
    END
  END tb_dmem_wdata[3]
  PIN tb_dmem_wdata[4]
    DIRECTION INPUT ;
    USE SIGNAL ;
    ANTENNAGATEAREA 0.159000 ;
    ANTENNADIFFAREA 0.434700 ;
    PORT
      LAYER met3 ;
        RECT 842.165 251.640 844.165 252.240 ;
    END
  END tb_dmem_wdata[4]
  PIN tb_dmem_wdata[5]
    DIRECTION INPUT ;
    USE SIGNAL ;
    ANTENNAGATEAREA 0.159000 ;
    ANTENNADIFFAREA 0.434700 ;
    PORT
      LAYER met3 ;
        RECT 842.165 231.240 844.165 231.840 ;
    END
  END tb_dmem_wdata[5]
  PIN tb_dmem_wdata[6]
    DIRECTION INPUT ;
    USE SIGNAL ;
    ANTENNAGATEAREA 0.159000 ;
    ANTENNADIFFAREA 0.434700 ;
    PORT
      LAYER met3 ;
        RECT 842.165 272.040 844.165 272.640 ;
    END
  END tb_dmem_wdata[6]
  PIN tb_dmem_wdata[7]
    DIRECTION INPUT ;
    USE SIGNAL ;
    ANTENNAGATEAREA 0.159000 ;
    ANTENNADIFFAREA 0.434700 ;
    PORT
      LAYER met3 ;
        RECT 842.165 268.640 844.165 269.240 ;
    END
  END tb_dmem_wdata[7]
  PIN tb_dmem_wdata[8]
    DIRECTION INPUT ;
    USE SIGNAL ;
    ANTENNAGATEAREA 0.159000 ;
    ANTENNADIFFAREA 0.434700 ;
    PORT
      LAYER met3 ;
        RECT 842.165 244.840 844.165 245.440 ;
    END
  END tb_dmem_wdata[8]
  PIN tb_dmem_wdata[9]
    DIRECTION INPUT ;
    USE SIGNAL ;
    ANTENNAGATEAREA 0.159000 ;
    ANTENNADIFFAREA 0.434700 ;
    PORT
      LAYER met3 ;
        RECT 842.165 248.240 844.165 248.840 ;
    END
  END tb_dmem_wdata[9]
  PIN tb_dmem_we
    DIRECTION INPUT ;
    USE SIGNAL ;
    ANTENNAGATEAREA 0.159000 ;
    ANTENNADIFFAREA 0.434700 ;
    PORT
      LAYER met3 ;
        RECT 842.165 377.440 844.165 378.040 ;
    END
  END tb_dmem_we
  PIN tb_imem_addr[0]
    DIRECTION INPUT ;
    USE SIGNAL ;
    ANTENNAGATEAREA 0.247500 ;
    ANTENNADIFFAREA 0.434700 ;
    PORT
      LAYER met3 ;
        RECT 0.000 159.840 2.000 160.440 ;
    END
  END tb_imem_addr[0]
  PIN tb_imem_addr[1]
    DIRECTION INPUT ;
    USE SIGNAL ;
    ANTENNAGATEAREA 0.247500 ;
    ANTENNADIFFAREA 0.434700 ;
    PORT
      LAYER met3 ;
        RECT 0.000 166.640 2.000 167.240 ;
    END
  END tb_imem_addr[1]
  PIN tb_imem_addr[2]
    DIRECTION INPUT ;
    USE SIGNAL ;
    ANTENNAGATEAREA 0.247500 ;
    ANTENNADIFFAREA 0.434700 ;
    PORT
      LAYER met3 ;
        RECT 0.000 173.440 2.000 174.040 ;
    END
  END tb_imem_addr[2]
  PIN tb_imem_addr[3]
    DIRECTION INPUT ;
    USE SIGNAL ;
    ANTENNAGATEAREA 0.247500 ;
    ANTENNADIFFAREA 0.434700 ;
    PORT
      LAYER met3 ;
        RECT 0.000 170.040 2.000 170.640 ;
    END
  END tb_imem_addr[3]
  PIN tb_imem_addr[4]
    DIRECTION INPUT ;
    USE SIGNAL ;
    ANTENNAGATEAREA 0.213000 ;
    ANTENNADIFFAREA 0.434700 ;
    PORT
      LAYER met3 ;
        RECT 0.000 302.640 2.000 303.240 ;
    END
  END tb_imem_addr[4]
  PIN tb_imem_addr[5]
    DIRECTION INPUT ;
    USE SIGNAL ;
    ANTENNAGATEAREA 0.213000 ;
    ANTENNADIFFAREA 0.434700 ;
    PORT
      LAYER met3 ;
        RECT 0.000 309.440 2.000 310.040 ;
    END
  END tb_imem_addr[5]
  PIN tb_imem_wdata[0]
    DIRECTION INPUT ;
    USE SIGNAL ;
    ANTENNAGATEAREA 0.213000 ;
    ANTENNADIFFAREA 0.434700 ;
    PORT
      LAYER met2 ;
        RECT 180.410 852.885 180.690 854.885 ;
    END
  END tb_imem_wdata[0]
  PIN tb_imem_wdata[10]
    DIRECTION INPUT ;
    USE SIGNAL ;
    ANTENNAGATEAREA 0.247500 ;
    ANTENNADIFFAREA 0.434700 ;
    PORT
      LAYER met3 ;
        RECT 0.000 584.840 2.000 585.440 ;
    END
  END tb_imem_wdata[10]
  PIN tb_imem_wdata[11]
    DIRECTION INPUT ;
    USE SIGNAL ;
    ANTENNAGATEAREA 0.213000 ;
    ANTENNADIFFAREA 0.434700 ;
    PORT
      LAYER met3 ;
        RECT 0.000 629.040 2.000 629.640 ;
    END
  END tb_imem_wdata[11]
  PIN tb_imem_wdata[12]
    DIRECTION INPUT ;
    USE SIGNAL ;
    ANTENNAGATEAREA 0.213000 ;
    ANTENNADIFFAREA 0.434700 ;
    PORT
      LAYER met3 ;
        RECT 0.000 591.640 2.000 592.240 ;
    END
  END tb_imem_wdata[12]
  PIN tb_imem_wdata[13]
    DIRECTION INPUT ;
    USE SIGNAL ;
    ANTENNAGATEAREA 0.247500 ;
    ANTENNADIFFAREA 0.434700 ;
    PORT
      LAYER met3 ;
        RECT 0.000 469.240 2.000 469.840 ;
    END
  END tb_imem_wdata[13]
  PIN tb_imem_wdata[14]
    DIRECTION INPUT ;
    USE SIGNAL ;
    ANTENNAGATEAREA 0.247500 ;
    ANTENNADIFFAREA 0.434700 ;
    PORT
      LAYER met2 ;
        RECT 347.850 0.000 348.130 2.000 ;
    END
  END tb_imem_wdata[14]
  PIN tb_imem_wdata[15]
    DIRECTION INPUT ;
    USE SIGNAL ;
    ANTENNAGATEAREA 0.247500 ;
    ANTENNADIFFAREA 0.434700 ;
    PORT
      LAYER met3 ;
        RECT 0.000 639.240 2.000 639.840 ;
    END
  END tb_imem_wdata[15]
  PIN tb_imem_wdata[16]
    DIRECTION INPUT ;
    USE SIGNAL ;
    ANTENNAGATEAREA 0.213000 ;
    ANTENNADIFFAREA 0.434700 ;
    PORT
      LAYER met3 ;
        RECT 0.000 540.640 2.000 541.240 ;
    END
  END tb_imem_wdata[16]
  PIN tb_imem_wdata[17]
    DIRECTION INPUT ;
    USE SIGNAL ;
    ANTENNAGATEAREA 0.247500 ;
    ANTENNADIFFAREA 0.434700 ;
    PORT
      LAYER met2 ;
        RECT 273.790 0.000 274.070 2.000 ;
    END
  END tb_imem_wdata[17]
  PIN tb_imem_wdata[18]
    DIRECTION INPUT ;
    USE SIGNAL ;
    ANTENNAGATEAREA 0.247500 ;
    ANTENNADIFFAREA 0.434700 ;
    PORT
      LAYER met2 ;
        RECT 305.990 0.000 306.270 2.000 ;
    END
  END tb_imem_wdata[18]
  PIN tb_imem_wdata[19]
    DIRECTION INPUT ;
    USE SIGNAL ;
    ANTENNAGATEAREA 0.247500 ;
    ANTENNADIFFAREA 0.434700 ;
    PORT
      LAYER met2 ;
        RECT 351.070 0.000 351.350 2.000 ;
    END
  END tb_imem_wdata[19]
  PIN tb_imem_wdata[1]
    DIRECTION INPUT ;
    USE SIGNAL ;
    ANTENNAGATEAREA 0.213000 ;
    ANTENNADIFFAREA 0.434700 ;
    PORT
      LAYER met3 ;
        RECT 0.000 669.840 2.000 670.440 ;
    END
  END tb_imem_wdata[1]
  PIN tb_imem_wdata[20]
    DIRECTION INPUT ;
    USE SIGNAL ;
    ANTENNAGATEAREA 0.213000 ;
    ANTENNADIFFAREA 0.434700 ;
    PORT
      LAYER met3 ;
        RECT 0.000 360.440 2.000 361.040 ;
    END
  END tb_imem_wdata[20]
  PIN tb_imem_wdata[21]
    DIRECTION INPUT ;
    USE SIGNAL ;
    ANTENNAGATEAREA 0.247500 ;
    ANTENNADIFFAREA 0.434700 ;
    PORT
      LAYER met2 ;
        RECT 277.010 0.000 277.290 2.000 ;
    END
  END tb_imem_wdata[21]
  PIN tb_imem_wdata[22]
    DIRECTION INPUT ;
    USE SIGNAL ;
    ANTENNAGATEAREA 0.213000 ;
    ANTENNADIFFAREA 0.434700 ;
    PORT
      LAYER met3 ;
        RECT 0.000 357.040 2.000 357.640 ;
    END
  END tb_imem_wdata[22]
  PIN tb_imem_wdata[23]
    DIRECTION INPUT ;
    USE SIGNAL ;
    ANTENNAGATEAREA 0.159000 ;
    ANTENNADIFFAREA 0.434700 ;
    PORT
      LAYER met2 ;
        RECT 260.910 0.000 261.190 2.000 ;
    END
  END tb_imem_wdata[23]
  PIN tb_imem_wdata[24]
    DIRECTION INPUT ;
    USE SIGNAL ;
    ANTENNAGATEAREA 0.213000 ;
    ANTENNADIFFAREA 0.434700 ;
    PORT
      LAYER met2 ;
        RECT 296.330 0.000 296.610 2.000 ;
    END
  END tb_imem_wdata[24]
  PIN tb_imem_wdata[25]
    DIRECTION INPUT ;
    USE SIGNAL ;
    ANTENNAGATEAREA 0.213000 ;
    ANTENNADIFFAREA 0.434700 ;
    PORT
      LAYER met3 ;
        RECT 0.000 95.240 2.000 95.840 ;
    END
  END tb_imem_wdata[25]
  PIN tb_imem_wdata[26]
    DIRECTION INPUT ;
    USE SIGNAL ;
    ANTENNAGATEAREA 0.213000 ;
    ANTENNADIFFAREA 0.434700 ;
    PORT
      LAYER met3 ;
        RECT 0.000 149.640 2.000 150.240 ;
    END
  END tb_imem_wdata[26]
  PIN tb_imem_wdata[27]
    DIRECTION INPUT ;
    USE SIGNAL ;
    ANTENNAGATEAREA 0.213000 ;
    ANTENNADIFFAREA 0.434700 ;
    PORT
      LAYER met3 ;
        RECT 0.000 98.640 2.000 99.240 ;
    END
  END tb_imem_wdata[27]
  PIN tb_imem_wdata[28]
    DIRECTION INPUT ;
    USE SIGNAL ;
    ANTENNAGATEAREA 0.213000 ;
    ANTENNADIFFAREA 0.434700 ;
    PORT
      LAYER met3 ;
        RECT 0.000 102.040 2.000 102.640 ;
    END
  END tb_imem_wdata[28]
  PIN tb_imem_wdata[29]
    DIRECTION INPUT ;
    USE SIGNAL ;
    ANTENNAGATEAREA 0.213000 ;
    ANTENNADIFFAREA 0.434700 ;
    PORT
      LAYER met3 ;
        RECT 0.000 156.440 2.000 157.040 ;
    END
  END tb_imem_wdata[29]
  PIN tb_imem_wdata[2]
    DIRECTION INPUT ;
    USE SIGNAL ;
    ANTENNAGATEAREA 0.213000 ;
    ANTENNADIFFAREA 0.434700 ;
    PORT
      LAYER met3 ;
        RECT 0.000 666.440 2.000 667.040 ;
    END
  END tb_imem_wdata[2]
  PIN tb_imem_wdata[30]
    DIRECTION INPUT ;
    USE SIGNAL ;
    ANTENNAGATEAREA 0.247500 ;
    ANTENNADIFFAREA 0.434700 ;
    PORT
      LAYER met3 ;
        RECT 0.000 163.240 2.000 163.840 ;
    END
  END tb_imem_wdata[30]
  PIN tb_imem_wdata[31]
    DIRECTION INPUT ;
    USE SIGNAL ;
    ANTENNAGATEAREA 0.247500 ;
    ANTENNADIFFAREA 0.434700 ;
    PORT
      LAYER met2 ;
        RECT 190.070 0.000 190.350 2.000 ;
    END
  END tb_imem_wdata[31]
  PIN tb_imem_wdata[3]
    DIRECTION INPUT ;
    USE SIGNAL ;
    ANTENNAGATEAREA 0.159000 ;
    ANTENNADIFFAREA 0.434700 ;
    PORT
      LAYER met3 ;
        RECT 0.000 646.040 2.000 646.640 ;
    END
  END tb_imem_wdata[3]
  PIN tb_imem_wdata[4]
    DIRECTION INPUT ;
    USE SIGNAL ;
    ANTENNAGATEAREA 0.159000 ;
    ANTENNADIFFAREA 0.434700 ;
    PORT
      LAYER met3 ;
        RECT 0.000 353.640 2.000 354.240 ;
    END
  END tb_imem_wdata[4]
  PIN tb_imem_wdata[5]
    DIRECTION INPUT ;
    USE SIGNAL ;
    ANTENNAGATEAREA 0.213000 ;
    ANTENNADIFFAREA 0.434700 ;
    PORT
      LAYER met3 ;
        RECT 0.000 343.440 2.000 344.040 ;
    END
  END tb_imem_wdata[5]
  PIN tb_imem_wdata[6]
    DIRECTION INPUT ;
    USE SIGNAL ;
    ANTENNAGATEAREA 0.159000 ;
    ANTENNADIFFAREA 0.434700 ;
    PORT
      LAYER met3 ;
        RECT 0.000 411.440 2.000 412.040 ;
    END
  END tb_imem_wdata[6]
  PIN tb_imem_wdata[7]
    DIRECTION INPUT ;
    USE SIGNAL ;
    ANTENNAGATEAREA 0.159000 ;
    ANTENNADIFFAREA 0.434700 ;
    PORT
      LAYER met3 ;
        RECT 0.000 476.040 2.000 476.640 ;
    END
  END tb_imem_wdata[7]
  PIN tb_imem_wdata[8]
    DIRECTION INPUT ;
    USE SIGNAL ;
    ANTENNAGATEAREA 0.159000 ;
    ANTENNADIFFAREA 0.434700 ;
    PORT
      LAYER met3 ;
        RECT 0.000 550.840 2.000 551.440 ;
    END
  END tb_imem_wdata[8]
  PIN tb_imem_wdata[9]
    DIRECTION INPUT ;
    USE SIGNAL ;
    ANTENNAGATEAREA 0.159000 ;
    ANTENNADIFFAREA 0.434700 ;
    PORT
      LAYER met3 ;
        RECT 0.000 527.040 2.000 527.640 ;
    END
  END tb_imem_wdata[9]
  PIN tb_imem_we
    DIRECTION INPUT ;
    USE SIGNAL ;
    ANTENNAGATEAREA 0.159000 ;
    ANTENNADIFFAREA 0.434700 ;
    PORT
      LAYER met3 ;
        RECT 0.000 306.040 2.000 306.640 ;
    END
  END tb_imem_we
  PIN tb_reg_rd_addr[0]
    DIRECTION INPUT ;
    USE SIGNAL ;
    ANTENNAGATEAREA 0.213000 ;
    ANTENNADIFFAREA 0.434700 ;
    PORT
      LAYER met2 ;
        RECT 708.490 0.000 708.770 2.000 ;
    END
  END tb_reg_rd_addr[0]
  PIN tb_reg_rd_addr[1]
    DIRECTION INPUT ;
    USE SIGNAL ;
    ANTENNAGATEAREA 0.159000 ;
    ANTENNADIFFAREA 0.434700 ;
    PORT
      LAYER met2 ;
        RECT 695.610 0.000 695.890 2.000 ;
    END
  END tb_reg_rd_addr[1]
  PIN tb_reg_rd_addr[2]
    DIRECTION INPUT ;
    USE SIGNAL ;
    ANTENNAGATEAREA 0.159000 ;
    ANTENNADIFFAREA 0.434700 ;
    PORT
      LAYER met2 ;
        RECT 702.050 0.000 702.330 2.000 ;
    END
  END tb_reg_rd_addr[2]
  PIN tb_reg_rd_data[0]
    DIRECTION OUTPUT ;
    USE SIGNAL ;
    ANTENNADIFFAREA 0.795200 ;
    PORT
      LAYER met2 ;
        RECT 470.210 0.000 470.490 2.000 ;
    END
  END tb_reg_rd_data[0]
  PIN tb_reg_rd_data[10]
    DIRECTION OUTPUT ;
    USE SIGNAL ;
    ANTENNADIFFAREA 0.795200 ;
    PORT
      LAYER met2 ;
        RECT 531.390 0.000 531.670 2.000 ;
    END
  END tb_reg_rd_data[10]
  PIN tb_reg_rd_data[11]
    DIRECTION OUTPUT ;
    USE SIGNAL ;
    ANTENNADIFFAREA 0.795200 ;
    PORT
      LAYER met2 ;
        RECT 689.170 0.000 689.450 2.000 ;
    END
  END tb_reg_rd_data[11]
  PIN tb_reg_rd_data[12]
    DIRECTION OUTPUT ;
    USE SIGNAL ;
    ANTENNADIFFAREA 0.795200 ;
    PORT
      LAYER met2 ;
        RECT 682.730 0.000 683.010 2.000 ;
    END
  END tb_reg_rd_data[12]
  PIN tb_reg_rd_data[13]
    DIRECTION OUTPUT ;
    USE SIGNAL ;
    ANTENNADIFFAREA 0.795200 ;
    PORT
      LAYER met2 ;
        RECT 685.950 0.000 686.230 2.000 ;
    END
  END tb_reg_rd_data[13]
  PIN tb_reg_rd_data[14]
    DIRECTION OUTPUT ;
    USE SIGNAL ;
    ANTENNADIFFAREA 0.795200 ;
    PORT
      LAYER met2 ;
        RECT 673.070 0.000 673.350 2.000 ;
    END
  END tb_reg_rd_data[14]
  PIN tb_reg_rd_data[15]
    DIRECTION OUTPUT ;
    USE SIGNAL ;
    ANTENNADIFFAREA 0.795200 ;
    PORT
      LAYER met2 ;
        RECT 663.410 0.000 663.690 2.000 ;
    END
  END tb_reg_rd_data[15]
  PIN tb_reg_rd_data[16]
    DIRECTION OUTPUT ;
    USE SIGNAL ;
    ANTENNADIFFAREA 0.795200 ;
    PORT
      LAYER met2 ;
        RECT 650.530 0.000 650.810 2.000 ;
    END
  END tb_reg_rd_data[16]
  PIN tb_reg_rd_data[17]
    DIRECTION OUTPUT ;
    USE SIGNAL ;
    ANTENNADIFFAREA 0.795200 ;
    PORT
      LAYER met2 ;
        RECT 676.290 0.000 676.570 2.000 ;
    END
  END tb_reg_rd_data[17]
  PIN tb_reg_rd_data[18]
    DIRECTION OUTPUT ;
    USE SIGNAL ;
    ANTENNADIFFAREA 0.795200 ;
    PORT
      LAYER met2 ;
        RECT 656.970 0.000 657.250 2.000 ;
    END
  END tb_reg_rd_data[18]
  PIN tb_reg_rd_data[19]
    DIRECTION OUTPUT ;
    USE SIGNAL ;
    ANTENNADIFFAREA 0.795200 ;
    PORT
      LAYER met2 ;
        RECT 660.190 0.000 660.470 2.000 ;
    END
  END tb_reg_rd_data[19]
  PIN tb_reg_rd_data[1]
    DIRECTION OUTPUT ;
    USE SIGNAL ;
    ANTENNADIFFAREA 0.795200 ;
    PORT
      LAYER met2 ;
        RECT 460.550 0.000 460.830 2.000 ;
    END
  END tb_reg_rd_data[1]
  PIN tb_reg_rd_data[20]
    DIRECTION OUTPUT ;
    USE SIGNAL ;
    ANTENNADIFFAREA 0.795200 ;
    PORT
      LAYER met2 ;
        RECT 669.850 0.000 670.130 2.000 ;
    END
  END tb_reg_rd_data[20]
  PIN tb_reg_rd_data[21]
    DIRECTION OUTPUT ;
    USE SIGNAL ;
    ANTENNADIFFAREA 0.795200 ;
    PORT
      LAYER met2 ;
        RECT 679.510 0.000 679.790 2.000 ;
    END
  END tb_reg_rd_data[21]
  PIN tb_reg_rd_data[22]
    DIRECTION OUTPUT ;
    USE SIGNAL ;
    ANTENNADIFFAREA 0.795200 ;
    PORT
      LAYER met2 ;
        RECT 705.270 0.000 705.550 2.000 ;
    END
  END tb_reg_rd_data[22]
  PIN tb_reg_rd_data[23]
    DIRECTION OUTPUT ;
    USE SIGNAL ;
    ANTENNADIFFAREA 0.795200 ;
    PORT
      LAYER met2 ;
        RECT 692.390 0.000 692.670 2.000 ;
    END
  END tb_reg_rd_data[23]
  PIN tb_reg_rd_data[24]
    DIRECTION OUTPUT ;
    USE SIGNAL ;
    ANTENNADIFFAREA 0.795200 ;
    PORT
      LAYER met2 ;
        RECT 727.810 0.000 728.090 2.000 ;
    END
  END tb_reg_rd_data[24]
  PIN tb_reg_rd_data[25]
    DIRECTION OUTPUT ;
    USE SIGNAL ;
    ANTENNADIFFAREA 0.795200 ;
    PORT
      LAYER met2 ;
        RECT 714.930 0.000 715.210 2.000 ;
    END
  END tb_reg_rd_data[25]
  PIN tb_reg_rd_data[26]
    DIRECTION OUTPUT ;
    USE SIGNAL ;
    ANTENNADIFFAREA 0.795200 ;
    PORT
      LAYER met2 ;
        RECT 718.150 0.000 718.430 2.000 ;
    END
  END tb_reg_rd_data[26]
  PIN tb_reg_rd_data[27]
    DIRECTION OUTPUT ;
    USE SIGNAL ;
    ANTENNADIFFAREA 0.795200 ;
    PORT
      LAYER met2 ;
        RECT 721.370 0.000 721.650 2.000 ;
    END
  END tb_reg_rd_data[27]
  PIN tb_reg_rd_data[28]
    DIRECTION OUTPUT ;
    USE SIGNAL ;
    ANTENNADIFFAREA 0.795200 ;
    PORT
      LAYER met2 ;
        RECT 724.590 0.000 724.870 2.000 ;
    END
  END tb_reg_rd_data[28]
  PIN tb_reg_rd_data[29]
    DIRECTION OUTPUT ;
    USE SIGNAL ;
    ANTENNADIFFAREA 0.795200 ;
    PORT
      LAYER met2 ;
        RECT 698.830 0.000 699.110 2.000 ;
    END
  END tb_reg_rd_data[29]
  PIN tb_reg_rd_data[2]
    DIRECTION OUTPUT ;
    USE SIGNAL ;
    ANTENNADIFFAREA 0.795200 ;
    PORT
      LAYER met2 ;
        RECT 466.990 0.000 467.270 2.000 ;
    END
  END tb_reg_rd_data[2]
  PIN tb_reg_rd_data[30]
    DIRECTION OUTPUT ;
    USE SIGNAL ;
    ANTENNADIFFAREA 0.795200 ;
    PORT
      LAYER met2 ;
        RECT 647.310 0.000 647.590 2.000 ;
    END
  END tb_reg_rd_data[30]
  PIN tb_reg_rd_data[31]
    DIRECTION OUTPUT ;
    USE SIGNAL ;
    ANTENNADIFFAREA 0.795200 ;
    PORT
      LAYER met2 ;
        RECT 653.750 0.000 654.030 2.000 ;
    END
  END tb_reg_rd_data[31]
  PIN tb_reg_rd_data[3]
    DIRECTION OUTPUT ;
    USE SIGNAL ;
    ANTENNADIFFAREA 0.795200 ;
    PORT
      LAYER met2 ;
        RECT 486.310 0.000 486.590 2.000 ;
    END
  END tb_reg_rd_data[3]
  PIN tb_reg_rd_data[4]
    DIRECTION OUTPUT ;
    USE SIGNAL ;
    ANTENNADIFFAREA 0.795200 ;
    PORT
      LAYER met2 ;
        RECT 502.410 0.000 502.690 2.000 ;
    END
  END tb_reg_rd_data[4]
  PIN tb_reg_rd_data[5]
    DIRECTION OUTPUT ;
    USE SIGNAL ;
    ANTENNADIFFAREA 0.795200 ;
    PORT
      LAYER met2 ;
        RECT 528.170 0.000 528.450 2.000 ;
    END
  END tb_reg_rd_data[5]
  PIN tb_reg_rd_data[6]
    DIRECTION OUTPUT ;
    USE SIGNAL ;
    ANTENNADIFFAREA 0.795200 ;
    PORT
      LAYER met2 ;
        RECT 644.090 0.000 644.370 2.000 ;
    END
  END tb_reg_rd_data[6]
  PIN tb_reg_rd_data[7]
    DIRECTION OUTPUT ;
    USE SIGNAL ;
    ANTENNADIFFAREA 0.795200 ;
    PORT
      LAYER met2 ;
        RECT 666.630 0.000 666.910 2.000 ;
    END
  END tb_reg_rd_data[7]
  PIN tb_reg_rd_data[8]
    DIRECTION OUTPUT ;
    USE SIGNAL ;
    ANTENNADIFFAREA 0.795200 ;
    PORT
      LAYER met2 ;
        RECT 495.970 0.000 496.250 2.000 ;
    END
  END tb_reg_rd_data[8]
  PIN tb_reg_rd_data[9]
    DIRECTION OUTPUT ;
    USE SIGNAL ;
    ANTENNADIFFAREA 0.795200 ;
    PORT
      LAYER met2 ;
        RECT 512.070 0.000 512.350 2.000 ;
    END
  END tb_reg_rd_data[9]
  OBS
      LAYER nwell ;
        RECT 5.330 10.795 838.770 843.285 ;
      LAYER li1 ;
        RECT 5.520 10.795 838.580 843.285 ;
      LAYER met1 ;
        RECT 5.130 10.640 838.580 843.440 ;
      LAYER met2 ;
        RECT 5.150 852.605 154.370 852.885 ;
        RECT 155.210 852.605 160.810 852.885 ;
        RECT 161.650 852.605 180.130 852.885 ;
        RECT 180.970 852.605 199.450 852.885 ;
        RECT 200.290 852.605 547.210 852.885 ;
        RECT 548.050 852.605 550.430 852.885 ;
        RECT 551.270 852.605 624.490 852.885 ;
        RECT 625.330 852.605 627.710 852.885 ;
        RECT 628.550 852.605 630.930 852.885 ;
        RECT 631.770 852.605 634.150 852.885 ;
        RECT 634.990 852.605 637.370 852.885 ;
        RECT 638.210 852.605 640.590 852.885 ;
        RECT 641.430 852.605 838.480 852.885 ;
        RECT 5.150 2.280 838.480 852.605 ;
        RECT 5.150 1.630 154.370 2.280 ;
        RECT 155.210 1.630 157.590 2.280 ;
        RECT 158.430 1.630 160.810 2.280 ;
        RECT 161.650 1.630 189.790 2.280 ;
        RECT 190.630 1.630 225.210 2.280 ;
        RECT 226.050 1.630 228.430 2.280 ;
        RECT 229.270 1.630 234.870 2.280 ;
        RECT 235.710 1.630 238.090 2.280 ;
        RECT 238.930 1.630 241.310 2.280 ;
        RECT 242.150 1.630 244.530 2.280 ;
        RECT 245.370 1.630 254.190 2.280 ;
        RECT 255.030 1.630 260.630 2.280 ;
        RECT 261.470 1.630 270.290 2.280 ;
        RECT 271.130 1.630 273.510 2.280 ;
        RECT 274.350 1.630 276.730 2.280 ;
        RECT 277.570 1.630 292.830 2.280 ;
        RECT 293.670 1.630 296.050 2.280 ;
        RECT 296.890 1.630 305.710 2.280 ;
        RECT 306.550 1.630 308.930 2.280 ;
        RECT 309.770 1.630 328.250 2.280 ;
        RECT 329.090 1.630 331.470 2.280 ;
        RECT 332.310 1.630 334.690 2.280 ;
        RECT 335.530 1.630 337.910 2.280 ;
        RECT 338.750 1.630 341.130 2.280 ;
        RECT 341.970 1.630 344.350 2.280 ;
        RECT 345.190 1.630 347.570 2.280 ;
        RECT 348.410 1.630 350.790 2.280 ;
        RECT 351.630 1.630 354.010 2.280 ;
        RECT 354.850 1.630 357.230 2.280 ;
        RECT 358.070 1.630 360.450 2.280 ;
        RECT 361.290 1.630 363.670 2.280 ;
        RECT 364.510 1.630 366.890 2.280 ;
        RECT 367.730 1.630 370.110 2.280 ;
        RECT 370.950 1.630 373.330 2.280 ;
        RECT 374.170 1.630 376.550 2.280 ;
        RECT 377.390 1.630 379.770 2.280 ;
        RECT 380.610 1.630 382.990 2.280 ;
        RECT 383.830 1.630 386.210 2.280 ;
        RECT 387.050 1.630 389.430 2.280 ;
        RECT 390.270 1.630 392.650 2.280 ;
        RECT 393.490 1.630 395.870 2.280 ;
        RECT 396.710 1.630 399.090 2.280 ;
        RECT 399.930 1.630 402.310 2.280 ;
        RECT 403.150 1.630 405.530 2.280 ;
        RECT 406.370 1.630 408.750 2.280 ;
        RECT 409.590 1.630 411.970 2.280 ;
        RECT 412.810 1.630 415.190 2.280 ;
        RECT 416.030 1.630 418.410 2.280 ;
        RECT 419.250 1.630 421.630 2.280 ;
        RECT 422.470 1.630 424.850 2.280 ;
        RECT 425.690 1.630 428.070 2.280 ;
        RECT 428.910 1.630 431.290 2.280 ;
        RECT 432.130 1.630 434.510 2.280 ;
        RECT 435.350 1.630 437.730 2.280 ;
        RECT 438.570 1.630 440.950 2.280 ;
        RECT 441.790 1.630 444.170 2.280 ;
        RECT 445.010 1.630 447.390 2.280 ;
        RECT 448.230 1.630 450.610 2.280 ;
        RECT 451.450 1.630 453.830 2.280 ;
        RECT 454.670 1.630 457.050 2.280 ;
        RECT 457.890 1.630 460.270 2.280 ;
        RECT 461.110 1.630 463.490 2.280 ;
        RECT 464.330 1.630 466.710 2.280 ;
        RECT 467.550 1.630 469.930 2.280 ;
        RECT 470.770 1.630 473.150 2.280 ;
        RECT 473.990 1.630 476.370 2.280 ;
        RECT 477.210 1.630 479.590 2.280 ;
        RECT 480.430 1.630 482.810 2.280 ;
        RECT 483.650 1.630 486.030 2.280 ;
        RECT 486.870 1.630 489.250 2.280 ;
        RECT 490.090 1.630 492.470 2.280 ;
        RECT 493.310 1.630 495.690 2.280 ;
        RECT 496.530 1.630 498.910 2.280 ;
        RECT 499.750 1.630 502.130 2.280 ;
        RECT 502.970 1.630 505.350 2.280 ;
        RECT 506.190 1.630 508.570 2.280 ;
        RECT 509.410 1.630 511.790 2.280 ;
        RECT 512.630 1.630 527.890 2.280 ;
        RECT 528.730 1.630 531.110 2.280 ;
        RECT 531.950 1.630 643.810 2.280 ;
        RECT 644.650 1.630 647.030 2.280 ;
        RECT 647.870 1.630 650.250 2.280 ;
        RECT 651.090 1.630 653.470 2.280 ;
        RECT 654.310 1.630 656.690 2.280 ;
        RECT 657.530 1.630 659.910 2.280 ;
        RECT 660.750 1.630 663.130 2.280 ;
        RECT 663.970 1.630 666.350 2.280 ;
        RECT 667.190 1.630 669.570 2.280 ;
        RECT 670.410 1.630 672.790 2.280 ;
        RECT 673.630 1.630 676.010 2.280 ;
        RECT 676.850 1.630 679.230 2.280 ;
        RECT 680.070 1.630 682.450 2.280 ;
        RECT 683.290 1.630 685.670 2.280 ;
        RECT 686.510 1.630 688.890 2.280 ;
        RECT 689.730 1.630 692.110 2.280 ;
        RECT 692.950 1.630 695.330 2.280 ;
        RECT 696.170 1.630 698.550 2.280 ;
        RECT 699.390 1.630 701.770 2.280 ;
        RECT 702.610 1.630 704.990 2.280 ;
        RECT 705.830 1.630 708.210 2.280 ;
        RECT 709.050 1.630 711.430 2.280 ;
        RECT 712.270 1.630 714.650 2.280 ;
        RECT 715.490 1.630 717.870 2.280 ;
        RECT 718.710 1.630 721.090 2.280 ;
        RECT 721.930 1.630 724.310 2.280 ;
        RECT 725.150 1.630 727.530 2.280 ;
        RECT 728.370 1.630 838.480 2.280 ;
      LAYER met3 ;
        RECT 2.000 827.240 842.165 843.365 ;
        RECT 2.400 825.840 842.165 827.240 ;
        RECT 2.000 670.840 842.165 825.840 ;
        RECT 2.400 669.440 842.165 670.840 ;
        RECT 2.000 667.440 842.165 669.440 ;
        RECT 2.400 666.040 842.165 667.440 ;
        RECT 2.000 647.040 842.165 666.040 ;
        RECT 2.400 645.640 842.165 647.040 ;
        RECT 2.000 640.240 842.165 645.640 ;
        RECT 2.400 638.840 842.165 640.240 ;
        RECT 2.000 633.440 842.165 638.840 ;
        RECT 2.400 632.040 842.165 633.440 ;
        RECT 2.000 630.040 842.165 632.040 ;
        RECT 2.400 628.640 842.165 630.040 ;
        RECT 2.000 592.640 842.165 628.640 ;
        RECT 2.400 591.240 842.165 592.640 ;
        RECT 2.000 585.840 842.165 591.240 ;
        RECT 2.400 584.440 842.165 585.840 ;
        RECT 2.000 551.840 842.165 584.440 ;
        RECT 2.400 550.440 842.165 551.840 ;
        RECT 2.000 545.040 842.165 550.440 ;
        RECT 2.400 543.640 842.165 545.040 ;
        RECT 2.000 541.640 842.165 543.640 ;
        RECT 2.400 540.240 842.165 541.640 ;
        RECT 2.000 528.040 842.165 540.240 ;
        RECT 2.400 526.640 842.165 528.040 ;
        RECT 2.000 504.240 842.165 526.640 ;
        RECT 2.400 502.840 842.165 504.240 ;
        RECT 2.000 477.040 842.165 502.840 ;
        RECT 2.400 475.640 842.165 477.040 ;
        RECT 2.000 470.240 842.165 475.640 ;
        RECT 2.400 468.840 842.165 470.240 ;
        RECT 2.000 412.440 842.165 468.840 ;
        RECT 2.400 411.040 842.165 412.440 ;
        RECT 2.000 381.840 842.165 411.040 ;
        RECT 2.000 380.440 841.765 381.840 ;
        RECT 2.000 378.440 842.165 380.440 ;
        RECT 2.000 377.040 841.765 378.440 ;
        RECT 2.000 375.040 842.165 377.040 ;
        RECT 2.000 373.640 841.765 375.040 ;
        RECT 2.000 371.640 842.165 373.640 ;
        RECT 2.000 370.240 841.765 371.640 ;
        RECT 2.000 368.240 842.165 370.240 ;
        RECT 2.000 366.840 841.765 368.240 ;
        RECT 2.000 364.840 842.165 366.840 ;
        RECT 2.000 363.440 841.765 364.840 ;
        RECT 2.000 361.440 842.165 363.440 ;
        RECT 2.400 360.040 841.765 361.440 ;
        RECT 2.000 358.040 842.165 360.040 ;
        RECT 2.400 356.640 841.765 358.040 ;
        RECT 2.000 354.640 842.165 356.640 ;
        RECT 2.400 353.240 841.765 354.640 ;
        RECT 2.000 351.240 842.165 353.240 ;
        RECT 2.000 349.840 841.765 351.240 ;
        RECT 2.000 347.840 842.165 349.840 ;
        RECT 2.000 346.440 841.765 347.840 ;
        RECT 2.000 344.440 842.165 346.440 ;
        RECT 2.400 343.040 841.765 344.440 ;
        RECT 2.000 341.040 842.165 343.040 ;
        RECT 2.000 339.640 841.765 341.040 ;
        RECT 2.000 337.640 842.165 339.640 ;
        RECT 2.000 336.240 841.765 337.640 ;
        RECT 2.000 334.240 842.165 336.240 ;
        RECT 2.000 332.840 841.765 334.240 ;
        RECT 2.000 330.840 842.165 332.840 ;
        RECT 2.000 329.440 841.765 330.840 ;
        RECT 2.000 327.440 842.165 329.440 ;
        RECT 2.000 326.040 841.765 327.440 ;
        RECT 2.000 324.040 842.165 326.040 ;
        RECT 2.000 322.640 841.765 324.040 ;
        RECT 2.000 320.640 842.165 322.640 ;
        RECT 2.000 319.240 841.765 320.640 ;
        RECT 2.000 317.240 842.165 319.240 ;
        RECT 2.000 315.840 841.765 317.240 ;
        RECT 2.000 313.840 842.165 315.840 ;
        RECT 2.000 312.440 841.765 313.840 ;
        RECT 2.000 310.440 842.165 312.440 ;
        RECT 2.400 309.040 841.765 310.440 ;
        RECT 2.000 307.040 842.165 309.040 ;
        RECT 2.400 305.640 841.765 307.040 ;
        RECT 2.000 303.640 842.165 305.640 ;
        RECT 2.400 302.240 841.765 303.640 ;
        RECT 2.000 300.240 842.165 302.240 ;
        RECT 2.000 298.840 841.765 300.240 ;
        RECT 2.000 296.840 842.165 298.840 ;
        RECT 2.000 295.440 841.765 296.840 ;
        RECT 2.000 293.440 842.165 295.440 ;
        RECT 2.000 292.040 841.765 293.440 ;
        RECT 2.000 290.040 842.165 292.040 ;
        RECT 2.000 288.640 841.765 290.040 ;
        RECT 2.000 286.640 842.165 288.640 ;
        RECT 2.000 285.240 841.765 286.640 ;
        RECT 2.000 283.240 842.165 285.240 ;
        RECT 2.000 281.840 841.765 283.240 ;
        RECT 2.000 279.840 842.165 281.840 ;
        RECT 2.000 278.440 841.765 279.840 ;
        RECT 2.000 276.440 842.165 278.440 ;
        RECT 2.000 275.040 841.765 276.440 ;
        RECT 2.000 273.040 842.165 275.040 ;
        RECT 2.000 271.640 841.765 273.040 ;
        RECT 2.000 269.640 842.165 271.640 ;
        RECT 2.000 268.240 841.765 269.640 ;
        RECT 2.000 266.240 842.165 268.240 ;
        RECT 2.000 264.840 841.765 266.240 ;
        RECT 2.000 262.840 842.165 264.840 ;
        RECT 2.000 261.440 841.765 262.840 ;
        RECT 2.000 259.440 842.165 261.440 ;
        RECT 2.000 258.040 841.765 259.440 ;
        RECT 2.000 256.040 842.165 258.040 ;
        RECT 2.000 254.640 841.765 256.040 ;
        RECT 2.000 252.640 842.165 254.640 ;
        RECT 2.000 251.240 841.765 252.640 ;
        RECT 2.000 249.240 842.165 251.240 ;
        RECT 2.000 247.840 841.765 249.240 ;
        RECT 2.000 245.840 842.165 247.840 ;
        RECT 2.000 244.440 841.765 245.840 ;
        RECT 2.000 242.440 842.165 244.440 ;
        RECT 2.000 241.040 841.765 242.440 ;
        RECT 2.000 239.040 842.165 241.040 ;
        RECT 2.000 237.640 841.765 239.040 ;
        RECT 2.000 235.640 842.165 237.640 ;
        RECT 2.000 234.240 841.765 235.640 ;
        RECT 2.000 232.240 842.165 234.240 ;
        RECT 2.000 230.840 841.765 232.240 ;
        RECT 2.000 228.840 842.165 230.840 ;
        RECT 2.000 227.440 841.765 228.840 ;
        RECT 2.000 225.440 842.165 227.440 ;
        RECT 2.000 224.040 841.765 225.440 ;
        RECT 2.000 222.040 842.165 224.040 ;
        RECT 2.000 220.640 841.765 222.040 ;
        RECT 2.000 218.640 842.165 220.640 ;
        RECT 2.000 217.240 841.765 218.640 ;
        RECT 2.000 215.240 842.165 217.240 ;
        RECT 2.000 213.840 841.765 215.240 ;
        RECT 2.000 211.840 842.165 213.840 ;
        RECT 2.000 210.440 841.765 211.840 ;
        RECT 2.000 208.440 842.165 210.440 ;
        RECT 2.000 207.040 841.765 208.440 ;
        RECT 2.000 205.040 842.165 207.040 ;
        RECT 2.000 203.640 841.765 205.040 ;
        RECT 2.000 201.640 842.165 203.640 ;
        RECT 2.000 200.240 841.765 201.640 ;
        RECT 2.000 198.240 842.165 200.240 ;
        RECT 2.000 196.840 841.765 198.240 ;
        RECT 2.000 194.840 842.165 196.840 ;
        RECT 2.000 193.440 841.765 194.840 ;
        RECT 2.000 191.440 842.165 193.440 ;
        RECT 2.000 190.040 841.765 191.440 ;
        RECT 2.000 188.040 842.165 190.040 ;
        RECT 2.000 186.640 841.765 188.040 ;
        RECT 2.000 184.640 842.165 186.640 ;
        RECT 2.000 183.240 841.765 184.640 ;
        RECT 2.000 174.440 842.165 183.240 ;
        RECT 2.400 173.040 842.165 174.440 ;
        RECT 2.000 171.040 842.165 173.040 ;
        RECT 2.400 169.640 842.165 171.040 ;
        RECT 2.000 167.640 842.165 169.640 ;
        RECT 2.400 166.240 842.165 167.640 ;
        RECT 2.000 164.240 842.165 166.240 ;
        RECT 2.400 162.840 842.165 164.240 ;
        RECT 2.000 160.840 842.165 162.840 ;
        RECT 2.400 159.440 842.165 160.840 ;
        RECT 2.000 157.440 842.165 159.440 ;
        RECT 2.400 156.040 842.165 157.440 ;
        RECT 2.000 150.640 842.165 156.040 ;
        RECT 2.400 149.240 842.165 150.640 ;
        RECT 2.000 103.040 842.165 149.240 ;
        RECT 2.400 101.640 842.165 103.040 ;
        RECT 2.000 99.640 842.165 101.640 ;
        RECT 2.400 98.240 842.165 99.640 ;
        RECT 2.000 96.240 842.165 98.240 ;
        RECT 2.400 94.840 842.165 96.240 ;
        RECT 2.000 62.240 842.165 94.840 ;
        RECT 2.000 60.840 841.765 62.240 ;
        RECT 2.000 10.715 842.165 60.840 ;
      LAYER met4 ;
        RECT 16.855 11.735 20.640 842.345 ;
        RECT 23.040 11.735 23.940 842.345 ;
        RECT 26.340 11.735 174.240 842.345 ;
        RECT 176.640 11.735 177.540 842.345 ;
        RECT 179.940 11.735 327.840 842.345 ;
        RECT 330.240 11.735 331.140 842.345 ;
        RECT 333.540 11.735 481.440 842.345 ;
        RECT 483.840 11.735 484.740 842.345 ;
        RECT 487.140 11.735 635.040 842.345 ;
        RECT 637.440 11.735 638.340 842.345 ;
        RECT 640.740 11.735 788.640 842.345 ;
        RECT 791.040 11.735 791.940 842.345 ;
        RECT 794.340 11.735 826.785 842.345 ;
      LAYER met5 ;
        RECT 70.500 306.900 221.140 315.300 ;
  END
END cpu_top
END LIBRARY

